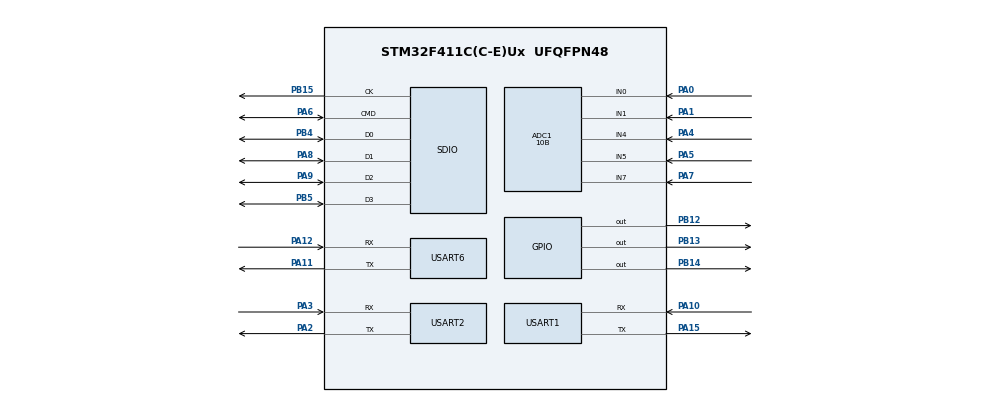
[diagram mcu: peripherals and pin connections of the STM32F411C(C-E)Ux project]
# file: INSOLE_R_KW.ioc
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Mcu.Family=STM32F4
Dma.USART2_RX.3.Mode=DMA_CIRCULAR
PA6.Mode=SD_4_bits_Wide_bus
ADC1.Rank-14\#ChannelRegularConversion=5
RCC.CortexFreq_Value=100000000
Dma.SDIO_RX.1.PeriphDataAlignment=DMA_PDATAALIGN_WORD
ADC1.ContinuousConvMode=ENABLE
VP_FATFS_VS_SDIO.Mode=SDIO
Dma.SDIO_RX.1.Mode=DMA_PFCTRL
Dma.SDIO_RX.1.Direction=DMA_PERIPH_TO_MEMORY
PA11.Mode=Asynchronous
Dma.SDIO_RX.1.Priority=DMA_PRIORITY_LOW
FREERTOS.configTICK_RATE_HZ=1000
ADC1.SamplingTime-12\#ChannelRegularConversion=ADC_SAMPLETIME_112CYCLES
PB13.Signal=GPIO_Output
PB15.Signal=SDIO_CK
ADC1.Channel-14\#ChannelRegularConversion=ADC_CHANNEL_7
TIM4.TIM_MasterOutputTrigger=TIM_TRGO_UPDATE
RCC.SYSCLKSource=RCC_SYSCLKSOURCE_PLLCLK
ProjectManager.StackSize=0x4000
Dma.SDIO_RX.1.Instance=DMA2_Stream3
Dma.SDIO_TX.2.Mode=DMA_PFCTRL
PA12.Signal=USART6_RX
Dma.SDIO_TX.2.MemDataAlignment=DMA_MDATAALIGN_WORD
ADC1.Channel-5\#ChannelRegularConversion=ADC_CHANNEL_0
NVIC.TIM5_IRQn=true\:0\:0\:false\:false\:true\:false\:false\:true
RCC.HCLKFreq_Value=100000000
ADC1.Resolution=ADC_RESOLUTION_10B
RCC.APB2TimFreq_Value=100000000
Dma.SDIO_RX.1.FIFOMode=DMA_FIFOMODE_ENABLE
Dma.ADC1.0.Direction=DMA_PERIPH_TO_MEMORY
ADC1.InjNumberOfConversion=0
NVIC.DMA2_Stream0_IRQn=true\:5\:0\:false\:false\:true\:true\:false\:true
Dma.ADC1.0.MemDataAlignment=DMA_MDATAALIGN_HALFWORD
RCC.AHBFreq_Value=100000000
RCC.HSE_VALUE=8000000
Dma.USART6_RX.4.Mode=DMA_NORMAL
PA15.Mode=Asynchronous
Dma.USART6_RX.4.Instance=DMA2_Stream1
PA6.GPIO_PuPd=GPIO_PULLUP
PB4.Mode=SD_4_bits_Wide_bus
Dma.ADC1.0.PeriphInc=DMA_PINC_DISABLE
PB5.Mode=SD_4_bits_Wide_bus
Dma.SDIO_TX.2.Direction=DMA_MEMORY_TO_PERIPH
PA8.Signal=SDIO_D1
SH.ADCx_IN0.0=ADC1_IN0,IN0
TIM4.Period=100-1
VP_FREERTOS_VS_CMSIS_V1.Mode=CMSIS_V1
Dma.USART2_RX.3.Direction=DMA_PERIPH_TO_MEMORY
Mcu.Package=UFQFPN48
Dma.USART6_RX.4.PeriphInc=DMA_PINC_DISABLE
PA6.Signal=SDIO_CMD
NVIC.TimeBase=TIM5_IRQn
USART2.VirtualMode=VM_ASYNC
USART6.VirtualMode=VM_ASYNC
ADC1.SamplingTime-13\#ChannelRegularConversion=ADC_SAMPLETIME_112CYCLES
Dma.SDIO_TX.2.PeriphBurst=DMA_PBURST_INC4
NVIC.TimeBaseIP=TIM5
PA10.Signal=USART1_RX
PA15.Signal=USART1_TX
Dma.SDIO_RX.1.PeriphBurst=DMA_PBURST_INC4
SH.ADCx_IN1.0=ADC1_IN1,IN1
Dma.USART2_RX.3.MemDataAlignment=DMA_MDATAALIGN_BYTE
Dma.USART6_RX.4.MemInc=DMA_MINC_ENABLE
Dma.Request2=SDIO_TX
Dma.Request1=SDIO_RX
RCC.APB1TimFreq_Value=100000000
Dma.Request4=USART6_RX
Dma.Request3=USART2_RX
Dma.ADC1.0.FIFOMode=DMA_FIFOMODE_DISABLE
NVIC.USART1_IRQn=true\:5\:0\:false\:false\:true\:true\:true\:true
Dma.Request0=ADC1
Dma.SDIO_TX.2.FIFOThreshold=DMA_FIFO_THRESHOLD_FULL
PB4.Signal=SDIO_D0
PA3.Signal=USART2_RX
Dma.USART6_RX.4.MemDataAlignment=DMA_MDATAALIGN_BYTE
ADC1.Channel-10\#ChannelRegularConversion=ADC_CHANNEL_1
Dma.SDIO_TX.2.MemInc=DMA_MINC_ENABLE
Dma.ADC1.0.Instance=DMA2_Stream0
FREERTOS.Tasks01=defaultTask,0,128,StartDefaultTask,Default,NULL
PA10.Mode=Asynchronous
ADC1.Rank-10\#ChannelRegularConversion=2
Dma.USART2_RX.3.Instance=DMA1_Stream5
Dma.USART6_RX.4.Priority=DMA_PRIORITY_LOW
VP_SYS_VS_tim5.Mode=TIM5
Dma.USART6_RX.4.PeriphDataAlignment=DMA_PDATAALIGN_BYTE
Dma.USART6_RX.4.FIFOMode=DMA_FIFOMODE_DISABLE
Dma.USART2_RX.3.PeriphDataAlignment=DMA_PDATAALIGN_BYTE
Dma.SDIO_TX.2.Instance=DMA2_Stream6
NVIC.DMA2_Stream1_IRQn=true\:5\:0\:false\:false\:true\:true\:false\:true
ADC1.Channel-13\#ChannelRegularConversion=ADC_CHANNEL_5
RCC.APB1CLKDivider=RCC_HCLK_DIV2
PA9.GPIO_PuPd=GPIO_PULLUP
NVIC.USART2_IRQn=true\:5\:0\:false\:false\:true\:true\:true\:true
NVIC.SDIO_IRQn=true\:5\:0\:false\:false\:true\:true\:true\:true
PA0-WKUP.Signal=ADCx_IN0
Dma.SDIO_RX.1.PeriphInc=DMA_PINC_DISABLE
NVIC.USART6_IRQn=true\:5\:0\:false\:false\:true\:true\:true\:true
PA3.Mode=Asynchronous
ADC1.Rank-13\#ChannelRegularConversion=4
Dma.ADC1.0.PeriphDataAlignment=DMA_PDATAALIGN_HALFWORD
PA9.Mode=SD_4_bits_Wide_bus
Dma.USART2_RX.3.FIFOMode=DMA_FIFOMODE_DISABLE
ProjectManager.TargetToolchain=MDK-ARM V5
NVIC.DMA1_Stream5_IRQn=true\:5\:0\:false\:false\:true\:true\:false\:true
SH.ADCx_IN7.0=ADC1_IN7,IN7
Dma.ADC1.0.Mode=DMA_CIRCULAR
Dma.ADC1.0.Priority=DMA_PRIORITY_LOW
PA9.Signal=SDIO_D2
Dma.SDIO_TX.2.PeriphDataAlignment=DMA_PDATAALIGN_WORD
PB4.GPIO_PuPd=GPIO_PULLUP
SDIO.ClockDiv=3
NVIC.DMA2_Stream3_IRQn=true\:5\:0\:false\:false\:true\:true\:false\:true
NVIC.DMA2_Stream6_IRQn=true\:5\:0\:false\:false\:true\:true\:false\:true
TIM4.Prescaler=1000-1
RCC.LSE_VALUE=32768
PA1.Signal=ADCx_IN1
Dma.SDIO_RX.1.MemDataAlignment=DMA_MDATAALIGN_WORD
Dma.SDIO_RX.1.FIFOThreshold=DMA_FIFO_THRESHOLD_FULL
PB14.Signal=GPIO_Output
PA5.Signal=ADCx_IN5
board=custom
Dma.SDIO_RX.1.MemBurst=DMA_MBURST_INC4
ADC1.Rank-12\#ChannelRegularConversion=3
RCC.VCOOutputFreq_Value=200000000
PB15.Mode=SD_4_bits_Wide_bus
ADC1.SamplingTime-14\#ChannelRegularConversion=ADC_SAMPLETIME_112CYCLES
ADC1.Channel-12\#ChannelRegularConversion=ADC_CHANNEL_4
RCC.APB2Freq_Value=100000000
SH.ADCx_IN4.0=ADC1_IN4,IN4
ADC1.DMAContinuousRequests=ENABLE
ADC1.SamplingTime-10\#ChannelRegularConversion=ADC_SAMPLETIME_112CYCLES
ADC1.NbrOfConversion=5
Mcu.Name=STM32F411C(C-E)Ux
PA2.Signal=USART2_TX
Dma.SDIO_TX.2.Priority=DMA_PRIORITY_LOW
FATFS._MAX_SS=4096
RCC.48MHZClocksFreq_Value=40000000
PA4.Signal=ADCx_IN4
RCC.SYSCLKFreq_VALUE=100000000
PB5.Signal=SDIO_D3
ADC1.master=1
PA12.Mode=Asynchronous
Dma.USART6_RX.4.Direction=DMA_PERIPH_TO_MEMORY
PB5.GPIO_PuPd=GPIO_PULLUP
USART1.VirtualMode=VM_ASYNC
PA11.Signal=USART6_TX
Dma.ADC1.0.MemInc=DMA_MINC_ENABLE
Dma.SDIO_TX.2.MemBurst=DMA_MBURST_INC4
ProjectManager.HeapSize=0x2000
Dma.SDIO_RX.1.MemInc=DMA_MINC_ENABLE
Dma.SDIO_TX.2.FIFOMode=DMA_FIFOMODE_ENABLE
Dma.USART2_RX.3.MemInc=DMA_MINC_ENABLE
Dma.USART2_RX.3.PeriphInc=DMA_PINC_DISABLE
ADC1.SamplingTime-5\#ChannelRegularConversion=ADC_SAMPLETIME_112CYCLES
RCC.HSI_VALUE=16000000
PA8.GPIO_PuPd=GPIO_PULLUP
SH.ADCx_IN5.0=ADC1_IN5,IN5
VP_TIM4_VS_ClockSourceINT.Mode=Internal
RCC.PLLQ=5
NVIC.PriorityGroup=NVIC_PRIORITYGROUP_4
ADC1.NbrOfConversionFlag=1
RCC.PLLM=8
RCC.PLLN=100
Dma.USART2_RX.3.Priority=DMA_PRIORITY_LOW
PA2.Mode=Asynchronous
Dma.SDIO_TX.2.PeriphInc=DMA_PINC_DISABLE
PA8.Mode=SD_4_bits_Wide_bus
NVIC.TIM4_IRQn=true\:5\:0\:false\:false\:true\:true\:true\:true
RCC.APB1Freq_Value=50000000
VP_CRC_VS_CRC.Mode=CRC_Activate
ADC1.Rank-5\#ChannelRegularConversion=1
PB12.Signal=GPIO_Output
PA7.Signal=ADCx_IN7

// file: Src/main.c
/* USER CODE BEGIN Header */

/*Definition in INSOLE Device Comm system
INSOLE_L : 10BYTE(FSR) + 4BYTE(ST/ED) + 6BYTE(UWB) + 2BYTE(CRC) = 22BYTE
***INSOLE_L : 10BYTE(FSR) + 4BYTE(ST/ED) + 12BYTE(UWB) + 2BYTE(CRC) = 28BYTE

INSOLE_R : 20BYTE(FSR) + 4BYTE(ST/ED) + 12BYTE(UWB) + 2BYTE(CRC)= 38BYTE
***INSOLE_R : 20BYTE(FSR) + 4BYTE(ST/ED) + 24BYTE(UWB) + 2BYTE(CRC)= 50BYTE

IMU      : 2Byte(TMR) + 20BYTE(FSR) + 18BYTE(IMU) + 12BYTE(UWB) + 4BYTE(ST/ED) + 2BYTE(CRC) = 58BYTE
***IMU      : 2Byte(TMR) + 20BYTE(FSR) + 18BYTE(IMU) + 24BYTE(UWB) + 4BYTE(ST/ED) + 2BYTE(CRC) = 70BYTE
*/
/**
  ******************************************************************************
  * @file           : main.c
  * @brief          : Main program body
  ******************************************************************************
  * @attention
  *
  * <h2><center>&copy; Copyright (c) 2020 STMicroelectronics.
  * All rights reserved.</center></h2>
  *
  * This software component is licensed by ST under Ultimate Liberty license
  * SLA0044, the "License"; You may not use this file except in compliance with
  * the License. You may obtain a copy of the License at:
  *                             www.st.com/SLA0044
  *
  ******************************************************************************
  */
/* USER CODE END Header */

#include "main.h"
#include "cmsis_os.h"
#include "fatfs.h"

/* USER CODE BEGIN Includes */
#include <stdio.h>
#include <string.h>
#include <stdbool.h>
/* USER CODE END Includes */

ADC_HandleTypeDef hadc1;
DMA_HandleTypeDef hdma_adc1;
CRC_HandleTypeDef hcrc;
SD_HandleTypeDef hsd;
DMA_HandleTypeDef hdma_sdio_rx;
DMA_HandleTypeDef hdma_sdio_tx;
TIM_HandleTypeDef htim4;
UART_HandleTypeDef huart1;
UART_HandleTypeDef huart2;
UART_HandleTypeDef huart6;
DMA_HandleTypeDef hdma_usart2_rx;
DMA_HandleTypeDef hdma_usart6_rx;
osThreadId defaultTaskHandle;

void SystemClock_Config(void);
static void MX_GPIO_Init(void);
static void MX_DMA_Init(void);
static void MX_ADC1_Init(void);
static void MX_USART1_UART_Init(void);
static void MX_USART2_UART_Init(void);
static void MX_CRC_Init(void);
static void MX_SDIO_SD_Init(void);
static void MX_TIM4_Init(void);
static void MX_USART6_UART_Init(void);
void StartDefaultTask(void const * argument);

/* USER CODE BEGIN 0 */
	//Communication buffers
	//DMA comm
	bool dma_connect = false;
	bool data_received_dma = true;

	uint8_t txdata[50]; //rx byffer
	uint8_t rxBuf_[28] = {0};
	uint8_t rxBuf_crc[28] = {0};

	//Inturrupt comm
	uint8_t buff_index = 0;
	bool received_flag = false;
	bool received_end = false;

	uint8_t rxBuf_sd[9];

	//UWB comm
	uint8_t Rxbuf_ino[16] = {0}; //rx from arduino
	uint8_t Rxbuf_ino_p[16] = {0}; //rx from arduino parsed

	//ADC DMA
	uint16_t adcValArray[5] = {0,};

	//crc
	uint32_t crcArray[8] = {0,}; // crc for save
	uint32_t crcArray_send[12] = {0,}; // crc for send
	uint16_t crcval = 0; // calculate crc data for test

	//buff calcualtion
	uint16_t cal_val = 0;
	uint16_t receive_val =0;

	//SD card variables
	extern char SDPath[4];   /* SD logical drive path */
	extern FATFS SDFatFS;    /* File system object for SD logical drive */
	extern FIL SDFile;       /* File object for SD */

	//FILE I/O operation
	FRESULT res;                                          /* FatFs function common result code */
	uint32_t byteswritten, bytesread;                     /* File write/read counts */
	uint8_t wtext[] = "test"; 			      /* File write start buffer */
	uint8_t rtext[100];                                   /* File read buffer */

	FATFS myFATAS;
	FIL myFILE;
	UINT testByte; 										  // error detection
	bool datasave_flg = true;
	bool ongoing_flg = false;

	bool sdcard_save = false;
	bool sdcard_save_check = true;
	bool sdcard_save_ongoing = false;

	//Timer
	bool _10ms_flg = false;
	bool _5ms_flg = false;
	bool _1000ms_flg = false;

	uint16_t ms_tmr = 0;
	uint16_t _100ms_tmr = 0;
	uint16_t ms_sv_tmr = 0;

	//wdg cnt
	uint8_t wdg_cnt = 0;
	uint8_t wdg_tmr = 0;

	//test val
	uint16_t test_val = 0;
	uint8_t k = 0;
	char str_testset[10];

/* USER CODE END 0 */

int main(void)
{

  /* MCU Configuration--------------------------------------------------------*/

  /* Reset of all peripherals, Initializes the Flash interface and the Systick. */
  HAL_Init();

  /* Configure the system clock */
  SystemClock_Config();

  /* Initialize all configured peripherals */
  MX_GPIO_Init();
  MX_DMA_Init();
  MX_ADC1_Init();
  MX_USART1_UART_Init();
  MX_USART2_UART_Init();
  MX_CRC_Init();
  MX_SDIO_SD_Init();
  MX_TIM4_Init();
  MX_USART6_UART_Init();
  MX_FATFS_Init();
  /* USER CODE BEGIN 2 */

  HAL_UART_Receive_DMA(&huart2, (uint8_t *)rxBuf_crc, 28); //interrupt dma mode only in the mcu data
  HAL_UART_Receive_DMA(&huart6, (uint8_t *)Rxbuf_ino, 16); //interrupt dma mode for arduino
  HAL_UART_Receive_IT(&huart1, (uint8_t *)rxBuf_sd, 9); //receive data from sd card

  HAL_ADC_Start_DMA(&hadc1,(uint32_t *)adcValArray, 5);
  HAL_TIM_Base_Start_IT(&htim4);
  /* USER CODE END 2 */

  /* Create the thread(s) */
  /* definition and creation of defaultTask */
  osThreadDef(defaultTask, StartDefaultTask, osPriorityNormal, 0, 128);
  defaultTaskHandle = osThreadCreate(osThread(defaultTask), NULL);

  /* Start scheduler */
  osKernelStart();

  /* We should never get here as control is now taken by the scheduler */
  /* Infinite loop */
  while (1)
  {

  }
}

void SystemClock_Config(void)
{
  RCC_OscInitTypeDef RCC_OscInitStruct = {0};
  RCC_ClkInitTypeDef RCC_ClkInitStruct = {0};

  /** Configure the main internal regulator output voltage
  */
  __HAL_RCC_PWR_CLK_ENABLE();
  __HAL_PWR_VOLTAGESCALING_CONFIG(PWR_REGULATOR_VOLTAGE_SCALE1);
  /** Initializes the CPU, AHB and APB busses clocks
  */
  RCC_OscInitStruct.OscillatorType = RCC_OSCILLATORTYPE_HSI;
  RCC_OscInitStruct.HSIState = RCC_HSI_ON;
  RCC_OscInitStruct.HSICalibrationValue = RCC_HSICALIBRATION_DEFAULT;
  RCC_OscInitStruct.PLL.PLLState = RCC_PLL_ON;
  RCC_OscInitStruct.PLL.PLLSource = RCC_PLLSOURCE_HSI;
  RCC_OscInitStruct.PLL.PLLM = 8;
  RCC_OscInitStruct.PLL.PLLN = 50;
  RCC_OscInitStruct.PLL.PLLP = RCC_PLLP_DIV2;
  RCC_OscInitStruct.PLL.PLLQ = 3;
  if (HAL_RCC_OscConfig(&RCC_OscInitStruct) != HAL_OK)
  {
    Error_Handler();
  }
  /** Initializes the CPU, AHB and APB busses clocks
  */
  RCC_ClkInitStruct.ClockType = RCC_CLOCKTYPE_HCLK|RCC_CLOCKTYPE_SYSCLK
                              |RCC_CLOCKTYPE_PCLK1|RCC_CLOCKTYPE_PCLK2;
  RCC_ClkInitStruct.SYSCLKSource = RCC_SYSCLKSOURCE_PLLCLK;
  RCC_ClkInitStruct.AHBCLKDivider = RCC_SYSCLK_DIV1;
  RCC_ClkInitStruct.APB1CLKDivider = RCC_HCLK_DIV2;
  RCC_ClkInitStruct.APB2CLKDivider = RCC_HCLK_DIV1;

  if (HAL_RCC_ClockConfig(&RCC_ClkInitStruct, FLASH_LATENCY_1) != HAL_OK)
  {
    Error_Handler();
  }
}

static void MX_ADC1_Init(void)
{

  ADC_ChannelConfTypeDef sConfig = {0};

  /** Configure the global features of the ADC (Clock, Resolution, Data Alignment and number of conversion)
  */
  hadc1.Instance = ADC1;
  hadc1.Init.ClockPrescaler = ADC_CLOCK_SYNC_PCLK_DIV2;
  hadc1.Init.Resolution = ADC_RESOLUTION_10B;
  hadc1.Init.ScanConvMode = ENABLE;
  hadc1.Init.ContinuousConvMode = ENABLE;
  hadc1.Init.DiscontinuousConvMode = DISABLE;
  hadc1.Init.ExternalTrigConvEdge = ADC_EXTERNALTRIGCONVEDGE_NONE;
  hadc1.Init.ExternalTrigConv = ADC_SOFTWARE_START;
  hadc1.Init.DataAlign = ADC_DATAALIGN_RIGHT;
  hadc1.Init.NbrOfConversion = 5;
  hadc1.Init.DMAContinuousRequests = ENABLE;
  hadc1.Init.EOCSelection = ADC_EOC_SINGLE_CONV;
  if (HAL_ADC_Init(&hadc1) != HAL_OK)
  {
    Error_Handler();
  }
  /** Configure for the selected ADC regular channel its corresponding rank in the sequencer and its sample time.
  */
  sConfig.Channel = ADC_CHANNEL_0;
  sConfig.Rank = 1;
  sConfig.SamplingTime = ADC_SAMPLETIME_112CYCLES;
  if (HAL_ADC_ConfigChannel(&hadc1, &sConfig) != HAL_OK)
  {
    Error_Handler();
  }
  /** Configure for the selected ADC regular channel its corresponding rank in the sequencer and its sample time.
  */
  sConfig.Channel = ADC_CHANNEL_1;
  sConfig.Rank = 2;
  if (HAL_ADC_ConfigChannel(&hadc1, &sConfig) != HAL_OK)
  {
    Error_Handler();
  }
  /** Configure for the selected ADC regular channel its corresponding rank in the sequencer and its sample time.
  */
  sConfig.Channel = ADC_CHANNEL_4;
  sConfig.Rank = 3;
  if (HAL_ADC_ConfigChannel(&hadc1, &sConfig) != HAL_OK)
  {
    Error_Handler();
  }
  /** Configure for the selected ADC regular channel its corresponding rank in the sequencer and its sample time.
  */
  sConfig.Channel = ADC_CHANNEL_5;
  sConfig.Rank = 4;
  if (HAL_ADC_ConfigChannel(&hadc1, &sConfig) != HAL_OK)
  {
    Error_Handler();
  }
  /** Configure for the selected ADC regular channel its corresponding rank in the sequencer and its sample time.
  */
  sConfig.Channel = ADC_CHANNEL_7;
  sConfig.Rank = 5;
  if (HAL_ADC_ConfigChannel(&hadc1, &sConfig) != HAL_OK)
  {
    Error_Handler();
  }

}

static void MX_CRC_Init(void)
{

  hcrc.Instance = CRC;
  if (HAL_CRC_Init(&hcrc) != HAL_OK)
  {
    Error_Handler();
  }

}

static void MX_SDIO_SD_Init(void)
{

  hsd.Instance = SDIO;
  hsd.Init.ClockEdge = SDIO_CLOCK_EDGE_RISING;
  hsd.Init.ClockBypass = SDIO_CLOCK_BYPASS_DISABLE;
  hsd.Init.ClockPowerSave = SDIO_CLOCK_POWER_SAVE_DISABLE;
  hsd.Init.BusWide = SDIO_BUS_WIDE_1B;
  hsd.Init.HardwareFlowControl = SDIO_HARDWARE_FLOW_CONTROL_DISABLE;
  hsd.Init.ClockDiv = 3;

}

static void MX_TIM4_Init(void)
{

  TIM_ClockConfigTypeDef sClockSourceConfig = {0};
  TIM_MasterConfigTypeDef sMasterConfig = {0};

  htim4.Instance = TIM4;
  htim4.Init.Prescaler = 5000-1;
  htim4.Init.CounterMode = TIM_COUNTERMODE_UP;
  htim4.Init.Period = 10-1;
  htim4.Init.ClockDivision = TIM_CLOCKDIVISION_DIV1;
  htim4.Init.AutoReloadPreload = TIM_AUTORELOAD_PRELOAD_DISABLE;
  if (HAL_TIM_Base_Init(&htim4) != HAL_OK)
  {
    Error_Handler();
  }
  sClockSourceConfig.ClockSource = TIM_CLOCKSOURCE_INTERNAL;
  if (HAL_TIM_ConfigClockSource(&htim4, &sClockSourceConfig) != HAL_OK)
  {
    Error_Handler();
  }
  sMasterConfig.MasterOutputTrigger = TIM_TRGO_RESET;
  sMasterConfig.MasterSlaveMode = TIM_MASTERSLAVEMODE_DISABLE;
  if (HAL_TIMEx_MasterConfigSynchronization(&htim4, &sMasterConfig) != HAL_OK)
  {
    Error_Handler();
  }

}

static void MX_USART1_UART_Init(void)
{

  huart1.Instance = USART1;
  huart1.Init.BaudRate = 115200;
  huart1.Init.WordLength = UART_WORDLENGTH_8B;
  huart1.Init.StopBits = UART_STOPBITS_1;
  huart1.Init.Parity = UART_PARITY_NONE;
  huart1.Init.Mode = UART_MODE_TX_RX;
  huart1.Init.HwFlowCtl = UART_HWCONTROL_NONE;
  huart1.Init.OverSampling = UART_OVERSAMPLING_16;
  if (HAL_UART_Init(&huart1) != HAL_OK)
  {
    Error_Handler();
  }

}

static void MX_USART2_UART_Init(void)
{

  huart2.Instance = USART2;
  huart2.Init.BaudRate = 115200;
  huart2.Init.WordLength = UART_WORDLENGTH_8B;
  huart2.Init.StopBits = UART_STOPBITS_1;
  huart2.Init.Parity = UART_PARITY_NONE;
  huart2.Init.Mode = UART_MODE_TX_RX;
  huart2.Init.HwFlowCtl = UART_HWCONTROL_NONE;
  huart2.Init.OverSampling = UART_OVERSAMPLING_16;
  if (HAL_UART_Init(&huart2) != HAL_OK)
  {
    Error_Handler();
  }

}

static void MX_USART6_UART_Init(void)
{

  huart6.Instance = USART6;
  huart6.Init.BaudRate = 115200;
  huart6.Init.WordLength = UART_WORDLENGTH_8B;
  huart6.Init.StopBits = UART_STOPBITS_1;
  huart6.Init.Parity = UART_PARITY_NONE;
  huart6.Init.Mode = UART_MODE_TX_RX;
  huart6.Init.HwFlowCtl = UART_HWCONTROL_NONE;
  huart6.Init.OverSampling = UART_OVERSAMPLING_16;
  if (HAL_UART_Init(&huart6) != HAL_OK)
  {
    Error_Handler();
  }

}

static void MX_DMA_Init(void)
{

  /* DMA controller clock enable */
  __HAL_RCC_DMA2_CLK_ENABLE();
  __HAL_RCC_DMA1_CLK_ENABLE();

  /* DMA interrupt init */
  /* DMA1_Stream5_IRQn interrupt configuration */
  HAL_NVIC_SetPriority(DMA1_Stream5_IRQn, 5, 0);
  HAL_NVIC_EnableIRQ(DMA1_Stream5_IRQn);
  /* DMA2_Stream0_IRQn interrupt configuration */
  HAL_NVIC_SetPriority(DMA2_Stream0_IRQn, 5, 0);
  HAL_NVIC_EnableIRQ(DMA2_Stream0_IRQn);
  /* DMA2_Stream1_IRQn interrupt configuration */
  HAL_NVIC_SetPriority(DMA2_Stream1_IRQn, 5, 0);
  HAL_NVIC_EnableIRQ(DMA2_Stream1_IRQn);
  /* DMA2_Stream3_IRQn interrupt configuration */
  HAL_NVIC_SetPriority(DMA2_Stream3_IRQn, 5, 0);
  HAL_NVIC_EnableIRQ(DMA2_Stream3_IRQn);
  /* DMA2_Stream6_IRQn interrupt configuration */
  HAL_NVIC_SetPriority(DMA2_Stream6_IRQn, 5, 0);
  HAL_NVIC_EnableIRQ(DMA2_Stream6_IRQn);

}

static void MX_GPIO_Init(void)
{
  GPIO_InitTypeDef GPIO_InitStruct = {0};

  /* GPIO Ports Clock Enable */
  __HAL_RCC_GPIOA_CLK_ENABLE();
  __HAL_RCC_GPIOB_CLK_ENABLE();

  /*Configure GPIO pin Output Level */
  HAL_GPIO_WritePin(GPIOB, GPIO_PIN_12|GPIO_PIN_13|GPIO_PIN_14, GPIO_PIN_RESET);

  /*Configure GPIO pins : PB12 PB13 PB14 */
  GPIO_InitStruct.Pin = GPIO_PIN_12|GPIO_PIN_13|GPIO_PIN_14;
  GPIO_InitStruct.Mode = GPIO_MODE_OUTPUT_PP;
  GPIO_InitStruct.Pull = GPIO_NOPULL;
  GPIO_InitStruct.Speed = GPIO_SPEED_FREQ_LOW;
  HAL_GPIO_Init(GPIOB, &GPIO_InitStruct);

}

/* USER CODE BEGIN 4 */

 void HAL_UART_RxCpltCallback(UART_HandleTypeDef *huart)
{
  /* Prevent unused argument(s) compilation warning */
  /* NOTE: This function should not be modified, when the callback is needed,
           the HAL_UART_RxCpltCallback could be implemented in the user file
  */
		//from
		if(huart->Instance == USART2){
				HAL_GPIO_TogglePin(GPIOB, GPIO_PIN_12);
				if(rxBuf_crc[0] == 0xFF && rxBuf_crc[1] == 0xFF){
					received_flag = true;
					dma_connect = true;
					memcpy(&rxBuf_[0], &rxBuf_crc[0], 28 );
				}
				else
				{
					received_flag = false;
					dma_connect = false;
					HAL_DMA_Abort(&hdma_usart2_rx);
				}
				test_val++;
		}
//		//from pc
//		if(huart->Instance == USART1){

//		uint8_t rxBuf_sd_p[9];

//		char rxlen = sizeof(rxBuf_sd);
//		for(char i =0; i < rxlen; i++)
//		{
//			char stx = i;
//			char etx = (i + rxlen - 1)%rxlen;
//			if(rxBuf_sd[stx] == '*' && rxBuf_sd[(etx)] == ';')
//			{
//					for(char j =0; j < rxlen; j++){
//						char k = (stx + j)%rxlen;
//						rxBuf_sd_p[j] = rxBuf_sd[k]; // data parse AND SAVE CUR
//					}
//				break;
//			}
//		}

//				if(rxBuf_sd_p[0] == '*' && rxBuf_sd_p[8] ==';'){
//						if(rxBuf_sd_p[1] == 's'){
//							char _txt[] = ".txt";
//							strncpy(str_testset, (const char*)rxBuf_sd+2,6);
//							strcat(str_testset,_txt);
//						//	sdcard_save = true;
//						HAL_UART_Transmit_IT(&huart2,rxBuf_sd_p,9); // data send to other bluetooth!
//						}
//						else if(rxBuf_sd_p[1] == 'e'){
//							HAL_GPIO_TogglePin(GPIOB, GPIO_PIN_14);
//						//	sdcard_save = false;
//						}
//				}
//				else{
//					memset(rxBuf_sd,0,sizeof(uint8_t)*9);
//				}
//	HAL_UART_Receive_IT(&huart1, (uint8_t *)rxBuf_sd, 9);
//
//		}
			// from arduino
		if(huart->Instance == USART6){
				//received search : start - start ?
				// data parse
				// dist data, power data
				char rxlen = sizeof(Rxbuf_ino);
				for(char i =0; i < rxlen; i++)
				{
					char stx = i;
					char stx_2 = (i+1)%rxlen;
					char etx = (i + rxlen - 1)%rxlen;
					char etx_2 = (i + rxlen - 2)%rxlen;
					if(Rxbuf_ino[stx] == 0xFF && Rxbuf_ino[(stx_2)] == 0xFF)
					{
						if(Rxbuf_ino[etx] == 0xFE && Rxbuf_ino[(etx_2)] == 0xFF)
						{
							for(char j =0; j < rxlen; j++){
								char k = (stx + j)%rxlen;
								Rxbuf_ino_p[j] = Rxbuf_ino[k]; // data parse AND SAVE CUR
							}

						break;
						}
					}
				}
		HAL_UART_Receive_DMA(&huart6, (uint8_t *)Rxbuf_ino, 16);
			}
}

void HAL_UART_TxCpltCallback(UART_HandleTypeDef *huart)
{
  /* Prevent unused argument(s) compilation warning */
	if(huart->Instance == USART2){

	}
	/* NOTE: This function should not be modified, when the callback is needed,
           the HAL_UART_TxCpltCallback could be implemented in the user file
	*/
}

void wdg_activate(){
	HAL_NVIC_SystemReset();
}

/* USER CODE END 4 */

void StartDefaultTask(void const * argument)
{
  /* USER CODE BEGIN 5 */
	//sd
	f_mount(&SDFatFS, (TCHAR const*)SDPath, 1);

//	if(f_open(&SDFile, "test32.txt", FA_CREATE_ALWAYS | FA_WRITE )== FR_OK){
//	}
//

  /* Infinite loop */
  for(;;)
  {
//	  	if(sdcard_save){
//				if(sdcard_save_check){
//					//HAL_GPIO_TogglePin(GPIOB, GPIO_PIN_14);
//					sdcard_save_check = false;
//					if(f_open(&SDFile, str_testset , FA_CREATE_ALWAYS | FA_WRITE ) == FR_OK){
//					sdcard_save_ongoing = true;
//					//HAL_GPIO_TogglePin(GPIOB, GPIO_PIN_14);
//					}
//				}
//			}
//		else{
//			if(!sdcard_save_check) {
//				f_close(&SDFile);
//				sdcard_save_check = true;
//				sdcard_save_ongoing = false;
//			}
//		}
	  if(_5ms_flg){
		_5ms_flg = false;

		txdata[0] = 0xFF;
		txdata[1] = 0xFF;
		//Right leg insole
		for(int i =0; i<5; i++){ // right / left -- insole + Imu dataset :
		char a = i*2;
		txdata[2+a] = adcValArray[i] >> 8;  //hi
		txdata[3+a] = adcValArray[i] & 0xFF;//lo
		}
		//Left leg insole from usart

		if(received_flag) {
		received_flag = false;
		uint8_t cprxBuf[28];
		memcpy(&cprxBuf[0], &rxBuf_[0], sizeof(uint8_t)*28);

		memset(crcArray,0,8*sizeof(crcArray[0]));
		memmove(&crcArray[0], &cprxBuf[2], sizeof(uint8_t)*22);
			char crc_begin = 24;
			char crc_end = 25;   //LLSB	 20 = FF 21 = FE 28 - 27 26
			receive_val = (int16_t)(((int16_t)cprxBuf[crc_begin] << 8) | cprxBuf[crc_end]);
			cal_val = (HAL_CRC_Calculate(&hcrc,crcArray,5)&0xffff);
			if(cal_val == receive_val)
			{
				memmove(&txdata[12], &cprxBuf[2], sizeof(uint8_t)*22);
			}
			else if( cal_val != receive_val)
			{
 				wdg_cnt ++;
				continue;
			}
		}
		for(int i =0; i < 12; i ++){
		txdata [34+i]  = Rxbuf_ino_p[2+i]; // signed short uwb data to txdata
		}

		memset(crcArray_send,0,12*sizeof(crcArray_send[0]));
		memcpy(&crcArray_send[0], &txdata[2] , 44);
		crcval = HAL_CRC_Calculate(&hcrc,crcArray_send,11)& 0xffff;

		txdata[46] = crcval >> 8;
		txdata[47] = crcval & 0xff;
		txdata[48] = 0xFF;
		txdata[49] = 0xFE;

		//	DATA SAVE TO LEFT LEG
			//5ms data save
//			for(int i =0; i<26; i++) {
//			f_printf(&SDFile, "%02x", txdata[i]);
//			}
//			f_printf(&SDFile, "\n");
//
//			f_close(&SDFile);

			// received data from pc

			// crc error
			HAL_UART_Transmit_IT(&huart1,txdata,50); //
		}
//	TRANSMIT DATA TO LEFT LEG
	}
  /* USER CODE END 5 */
}

 /**
  * @brief  Period elapsed callback in non blocking mode
  * @note   This function is called  when TIM5 interrupt took place, inside
  * HAL_TIM_IRQHandler(). It makes a direct call to HAL_IncTick() to increment
  * a global variable "uwTick" used as application time base.
  * @param  htim : TIM handle
  * @retval None
  */
void HAL_TIM_PeriodElapsedCallback(TIM_HandleTypeDef *htim)
{
  if (htim->Instance == TIM5) {
    HAL_IncTick();
  }
  /* USER CODE BEGIN Callback 1 */
 	if(htim ->Instance  == TIM4){
		ms_tmr ++;
		_100ms_tmr++;
		ms_sv_tmr++;

 		if(ms_tmr % 5 == 0){
			_5ms_flg = true;
			ms_tmr = 0;
		}
		if(_100ms_tmr % 100 == 0){ // watchdog tmr
			ongoing_flg = true;
			_100ms_tmr = 0;
		}

		if(ms_sv_tmr % 100 == 0){ // 10sec later - data save -> will change mode in the pc data
			datasave_flg = false;
			if(!dma_connect) HAL_UART_Receive_DMA(&huart2, (uint8_t *)rxBuf_crc, 28); //interrupt dma mode only in the mcu data

			ms_sv_tmr = 0;
		}
	}
  /* USER CODE END Callback 1 */
}

void Error_Handler(void)
{
}

/************************ (C) COPYRIGHT STMicroelectronics *****END OF FILE****/
